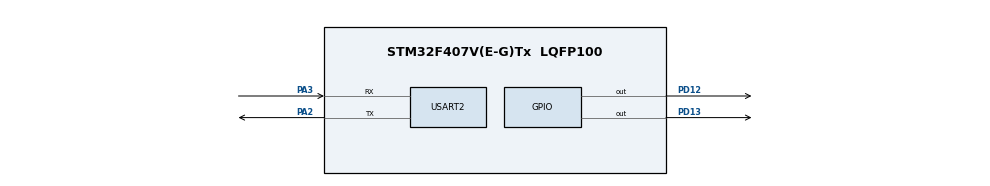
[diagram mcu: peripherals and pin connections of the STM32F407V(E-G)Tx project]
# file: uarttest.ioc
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Dma.Request0=USART2_RX
Dma.USART2_RX.0.Direction=DMA_PERIPH_TO_MEMORY
Dma.USART2_RX.0.FIFOMode=DMA_FIFOMODE_DISABLE
Dma.USART2_RX.0.Instance=DMA1_Stream5
Dma.USART2_RX.0.MemDataAlignment=DMA_MDATAALIGN_BYTE
Dma.USART2_RX.0.MemInc=DMA_MINC_ENABLE
Dma.USART2_RX.0.Mode=DMA_NORMAL
Dma.USART2_RX.0.PeriphDataAlignment=DMA_PDATAALIGN_BYTE
Dma.USART2_RX.0.PeriphInc=DMA_PINC_DISABLE
Dma.USART2_RX.0.Priority=DMA_PRIORITY_LOW
Mcu.Family=STM32F4
Mcu.Name=STM32F407V(E-G)Tx
Mcu.Package=LQFP100
NVIC.DMA1_Stream5_IRQn=true\:0\:0\:false\:false\:true\:false
NVIC.PriorityGroup=NVIC_PRIORITYGROUP_0
NVIC.USART2_IRQn=true\:0\:0\:false\:false\:true\:true
PA2.Mode=Asynchronous
PA2.Signal=USART2_TX
PA3.Mode=Asynchronous
PA3.Signal=USART2_RX
PD12.Signal=GPIO_Output
PD13.Signal=GPIO_Output
ProjectManager.HeapSize=0x200
ProjectManager.StackSize=0x400
ProjectManager.TargetToolchain=TrueSTUDIO
RCC.48MHZClocksFreq_Value=48000000
RCC.AHBFreq_Value=168000000
RCC.APB1CLKDivider=RCC_HCLK_DIV4
RCC.APB1Freq_Value=42000000
RCC.APB1TimFreq_Value=84000000
RCC.APB2CLKDivider=RCC_HCLK_DIV2
RCC.APB2Freq_Value=84000000
RCC.APB2TimFreq_Value=168000000
RCC.CortexFreq_Value=168000000
RCC.HCLKFreq_Value=168000000
RCC.HSE_VALUE=8000000
RCC.HSI_VALUE=16000000
RCC.LSE_VALUE=32768
RCC.PLLM=8
RCC.PLLN=168
RCC.PLLQ=7
RCC.SYSCLKFreq_VALUE=168000000
RCC.SYSCLKSource=RCC_SYSCLKSOURCE_PLLCLK
RCC.VCOOutputFreq_Value=336000000
USART2.VirtualMode=VM_ASYNC
board=STM32F4DISCOVERY

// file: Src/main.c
/**
  ******************************************************************************
  * @file           : main.c
  * @brief          : Main program body
  ******************************************************************************
  ** This notice applies to any and all portions of this file
  * that are not between comment pairs USER CODE BEGIN and
  * USER CODE END. Other portions of this file, whether
  * inserted by the user or by software development tools
  * are owned by their respective copyright owners.
  *
  * COPYRIGHT(c) 2018 STMicroelectronics
  *
  * Redistribution and use in source and binary forms, with or without modification,
  * are permitted provided that the following conditions are met:
  *   1. Redistributions of source code must retain the above copyright notice,
  *      this list of conditions and the following disclaimer.
  *   2. Redistributions in binary form must reproduce the above copyright notice,
  *      this list of conditions and the following disclaimer in the documentation
  *      and/or other materials provided with the distribution.
  *   3. Neither the name of STMicroelectronics nor the names of its contributors
  *      may be used to endorse or promote products derived from this software
  *      without specific prior written permission.
  *
  * THIS SOFTWARE IS PROVIDED BY THE COPYRIGHT HOLDERS AND CONTRIBUTORS "AS IS"
  * AND ANY EXPRESS OR IMPLIED WARRANTIES, INCLUDING, BUT NOT LIMITED TO, THE
  * IMPLIED WARRANTIES OF MERCHANTABILITY AND FITNESS FOR A PARTICULAR PURPOSE ARE
  * DISCLAIMED. IN NO EVENT SHALL THE COPYRIGHT HOLDER OR CONTRIBUTORS BE LIABLE
  * FOR ANY DIRECT, INDIRECT, INCIDENTAL, SPECIAL, EXEMPLARY, OR CONSEQUENTIAL
  * DAMAGES (INCLUDING, BUT NOT LIMITED TO, PROCUREMENT OF SUBSTITUTE GOODS OR
  * SERVICES; LOSS OF USE, DATA, OR PROFITS; OR BUSINESS INTERRUPTION) HOWEVER
  * CAUSED AND ON ANY THEORY OF LIABILITY, WHETHER IN CONTRACT, STRICT LIABILITY,
  * OR TORT (INCLUDING NEGLIGENCE OR OTHERWISE) ARISING IN ANY WAY OUT OF THE USE
  * OF THIS SOFTWARE, EVEN IF ADVISED OF THE POSSIBILITY OF SUCH DAMAGE.
  *
  ******************************************************************************
  */
#include "main.h"
#include "stm32f4xx_hal.h"

/* USER CODE BEGIN Includes */
#include <string.h>
/* USER CODE END Includes */

UART_HandleTypeDef huart2;
DMA_HandleTypeDef hdma_usart2_rx;

/* USER CODE BEGIN PV */
/* Private variables ---------------------------------------------------------*/

/* USER CODE END PV */

void SystemClock_Config(void);
static void MX_GPIO_Init(void);
static void MX_DMA_Init(void);
static void MX_USART2_UART_Init(void);

/* USER CODE BEGIN PFP */
/* Private function prototypes -----------------------------------------------*/

/* USER CODE END PFP */

int main(void)
{

  /* MCU Configuration----------------------------------------------------------*/

  /* Reset of all peripherals, Initializes the Flash interface and the Systick. */
  HAL_Init();

  /* Configure the system clock */
  SystemClock_Config();

  /* Initialize all configured peripherals */
  MX_GPIO_Init();
  MX_DMA_Init();
  MX_USART2_UART_Init();
  /* USER CODE BEGIN 2 */
  //char txData[30] = "please show me the value\r\n";
  absenc = 10.123;
  /* USER CODE END 2 */

  /* Infinite loop */
  while (1)
  {

  /* USER CODE BEGIN 3 */
	  //absenc=10.12344;
	  absenc_conv=absenc * 1000;
	  len=sprintf(txData, "This is encodervalue: %d\r\n", absenc_conv);
	  //HAL_UART_Transmit(&huart2, (uint8_t *)txData, strlen(txData), 100);
	  HAL_UART_Transmit(&huart2, (uint8_t *)txData, len, 100);
	  //HAL_UART_Transmit(&huart2, encoderdata, 4, 10);
	  HAL_Delay(2);
	  absenc= absenc+ 0.001;
  }
  /* USER CODE END 3 */

}

void SystemClock_Config(void)
{

  RCC_OscInitTypeDef RCC_OscInitStruct;
  RCC_ClkInitTypeDef RCC_ClkInitStruct;

    /**Configure the main internal regulator output voltage
    */
  __HAL_RCC_PWR_CLK_ENABLE();

  __HAL_PWR_VOLTAGESCALING_CONFIG(PWR_REGULATOR_VOLTAGE_SCALE1);

    /**Initializes the CPU, AHB and APB busses clocks
    */
  RCC_OscInitStruct.OscillatorType = RCC_OSCILLATORTYPE_HSI;
  RCC_OscInitStruct.HSIState = RCC_HSI_ON;
  RCC_OscInitStruct.HSICalibrationValue = 16;
  RCC_OscInitStruct.PLL.PLLState = RCC_PLL_ON;
  RCC_OscInitStruct.PLL.PLLSource = RCC_PLLSOURCE_HSI;
  RCC_OscInitStruct.PLL.PLLM = 8;
  RCC_OscInitStruct.PLL.PLLN = 50;
  RCC_OscInitStruct.PLL.PLLP = RCC_PLLP_DIV4;
  RCC_OscInitStruct.PLL.PLLQ = 7;
  if (HAL_RCC_OscConfig(&RCC_OscInitStruct) != HAL_OK)
  {
    _Error_Handler(__FILE__, __LINE__);
  }

    /**Initializes the CPU, AHB and APB busses clocks
    */
  RCC_ClkInitStruct.ClockType = RCC_CLOCKTYPE_HCLK|RCC_CLOCKTYPE_SYSCLK
                              |RCC_CLOCKTYPE_PCLK1|RCC_CLOCKTYPE_PCLK2;
  RCC_ClkInitStruct.SYSCLKSource = RCC_SYSCLKSOURCE_PLLCLK;
  RCC_ClkInitStruct.AHBCLKDivider = RCC_SYSCLK_DIV1;
  RCC_ClkInitStruct.APB1CLKDivider = RCC_HCLK_DIV4;
  RCC_ClkInitStruct.APB2CLKDivider = RCC_HCLK_DIV2;

  if (HAL_RCC_ClockConfig(&RCC_ClkInitStruct, FLASH_LATENCY_0) != HAL_OK)
  {
    _Error_Handler(__FILE__, __LINE__);
  }

    /**Configure the Systick interrupt time
    */
  HAL_SYSTICK_Config(HAL_RCC_GetHCLKFreq()/1000);

    /**Configure the Systick
    */
  HAL_SYSTICK_CLKSourceConfig(SYSTICK_CLKSOURCE_HCLK);

  /* SysTick_IRQn interrupt configuration */
  HAL_NVIC_SetPriority(SysTick_IRQn, 0, 0);
}

/* USART2 init function */
static void MX_USART2_UART_Init(void)
{

  huart2.Instance = USART2;
  huart2.Init.BaudRate = 115200;
  huart2.Init.WordLength = UART_WORDLENGTH_8B;
  huart2.Init.StopBits = UART_STOPBITS_1;
  huart2.Init.Parity = UART_PARITY_NONE;
  huart2.Init.Mode = UART_MODE_TX_RX;
  huart2.Init.HwFlowCtl = UART_HWCONTROL_NONE;
  huart2.Init.OverSampling = UART_OVERSAMPLING_16;
  if (HAL_UART_Init(&huart2) != HAL_OK)
  {
    _Error_Handler(__FILE__, __LINE__);
  }

}

static void MX_DMA_Init(void)
{
  /* DMA controller clock enable */
  __HAL_RCC_DMA1_CLK_ENABLE();

  /* DMA interrupt init */
  /* DMA1_Stream5_IRQn interrupt configuration */
  HAL_NVIC_SetPriority(DMA1_Stream5_IRQn, 0, 0);
  HAL_NVIC_EnableIRQ(DMA1_Stream5_IRQn);

}

/** Configure pins as
        * Analog
        * Input
        * Output
        * EVENT_OUT
        * EXTI
*/
static void MX_GPIO_Init(void)
{

  GPIO_InitTypeDef GPIO_InitStruct;

  /* GPIO Ports Clock Enable */
  __HAL_RCC_GPIOA_CLK_ENABLE();
  __HAL_RCC_GPIOD_CLK_ENABLE();

  /*Configure GPIO pin Output Level */
  HAL_GPIO_WritePin(GPIOD, GPIO_PIN_12|GPIO_PIN_13, GPIO_PIN_RESET);

  /*Configure GPIO pins : PD12 PD13 */
  GPIO_InitStruct.Pin = GPIO_PIN_12|GPIO_PIN_13;
  GPIO_InitStruct.Mode = GPIO_MODE_OUTPUT_PP;
  GPIO_InitStruct.Pull = GPIO_NOPULL;
  GPIO_InitStruct.Speed = GPIO_SPEED_FREQ_LOW;
  HAL_GPIO_Init(GPIOD, &GPIO_InitStruct);

}

void _Error_Handler(char *file, int line)
{
  while(1)
  {
  }
}

/************************ (C) COPYRIGHT STMicroelectronics *****END OF FILE****/
